VERSION 5.7 ;
  NOWIREEXTENSIONATPIN ON ;
  DIVIDERCHAR "/" ;
  BUSBITCHARS "[]" ;
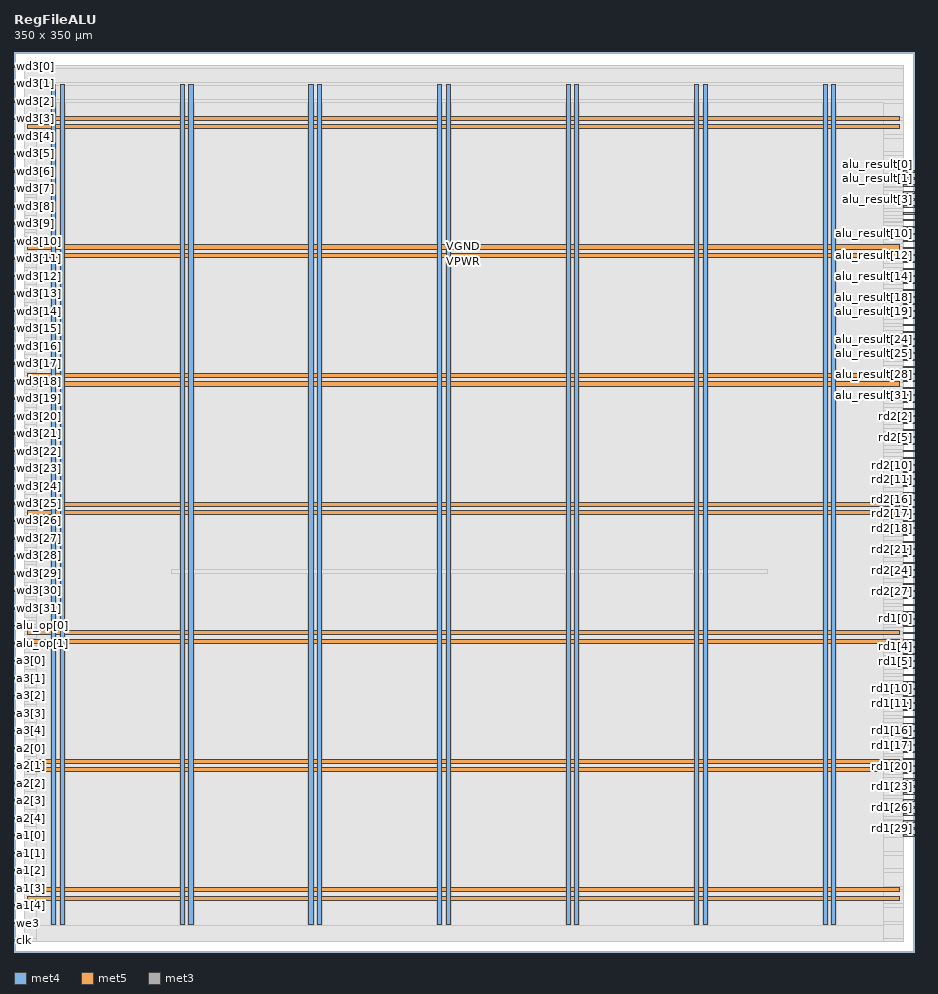
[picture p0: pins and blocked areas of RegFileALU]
MACRO RegFileALU
  CLASS BLOCK ;
  FOREIGN RegFileALU ;
  ORIGIN 0.000 0.000 ;
  SIZE 350.000 BY 350.000 ;
  PIN VGND
    DIRECTION INOUT ;
    USE GROUND ;
    PORT
      LAYER met4 ;
        RECT 18.020 10.640 19.620 337.520 ;
    END
    PORT
      LAYER met4 ;
        RECT 68.020 10.640 69.620 337.520 ;
    END
    PORT
      LAYER met4 ;
        RECT 118.020 10.640 119.620 337.520 ;
    END
    PORT
      LAYER met4 ;
        RECT 168.020 10.640 169.620 337.520 ;
    END
    PORT
      LAYER met4 ;
        RECT 218.020 10.640 219.620 337.520 ;
    END
    PORT
      LAYER met4 ;
        RECT 268.020 10.640 269.620 337.520 ;
    END
    PORT
      LAYER met4 ;
        RECT 318.020 10.640 319.620 337.520 ;
    END
    PORT
      LAYER met5 ;
        RECT 5.280 23.380 344.320 24.980 ;
    END
    PORT
      LAYER met5 ;
        RECT 5.280 73.380 344.320 74.980 ;
    END
    PORT
      LAYER met5 ;
        RECT 5.280 123.380 344.320 124.980 ;
    END
    PORT
      LAYER met5 ;
        RECT 5.280 173.380 344.320 174.980 ;
    END
    PORT
      LAYER met5 ;
        RECT 5.280 223.380 344.320 224.980 ;
    END
    PORT
      LAYER met5 ;
        RECT 5.280 273.380 344.320 274.980 ;
    END
    PORT
      LAYER met5 ;
        RECT 5.280 323.380 344.320 324.980 ;
    END
  END VGND
  PIN VPWR
    DIRECTION INOUT ;
    USE POWER ;
    PORT
      LAYER met4 ;
        RECT 14.720 10.640 16.320 337.520 ;
    END
    PORT
      LAYER met4 ;
        RECT 64.720 10.640 66.320 337.520 ;
    END
    PORT
      LAYER met4 ;
        RECT 114.720 10.640 116.320 337.520 ;
    END
    PORT
      LAYER met4 ;
        RECT 164.720 10.640 166.320 337.520 ;
    END
    PORT
      LAYER met4 ;
        RECT 214.720 10.640 216.320 337.520 ;
    END
    PORT
      LAYER met4 ;
        RECT 264.720 10.640 266.320 337.520 ;
    END
    PORT
      LAYER met4 ;
        RECT 314.720 10.640 316.320 337.520 ;
    END
    PORT
      LAYER met5 ;
        RECT 5.280 20.080 344.320 21.680 ;
    END
    PORT
      LAYER met5 ;
        RECT 5.280 70.080 344.320 71.680 ;
    END
    PORT
      LAYER met5 ;
        RECT 5.280 120.080 344.320 121.680 ;
    END
    PORT
      LAYER met5 ;
        RECT 5.280 170.080 344.320 171.680 ;
    END
    PORT
      LAYER met5 ;
        RECT 5.280 220.080 344.320 221.680 ;
    END
    PORT
      LAYER met5 ;
        RECT 5.280 270.080 344.320 271.680 ;
    END
    PORT
      LAYER met5 ;
        RECT 5.280 320.080 344.320 321.680 ;
    END
  END VPWR
  PIN a1[0]
    DIRECTION INPUT ;
    USE SIGNAL ;
    ANTENNAGATEAREA 0.196500 ;
    ANTENNADIFFAREA 0.434700 ;
    PORT
      LAYER met3 ;
        RECT 0.000 44.920 4.000 45.520 ;
    END
  END a1[0]
  PIN a1[1]
    DIRECTION INPUT ;
    USE SIGNAL ;
    ANTENNAGATEAREA 0.196500 ;
    ANTENNADIFFAREA 0.434700 ;
    PORT
      LAYER met3 ;
        RECT 0.000 38.120 4.000 38.720 ;
    END
  END a1[1]
  PIN a1[2]
    DIRECTION INPUT ;
    USE SIGNAL ;
    ANTENNAGATEAREA 0.126000 ;
    ANTENNADIFFAREA 0.434700 ;
    PORT
      LAYER met3 ;
        RECT 0.000 31.320 4.000 31.920 ;
    END
  END a1[2]
  PIN a1[3]
    DIRECTION INPUT ;
    USE SIGNAL ;
    ANTENNAGATEAREA 0.213000 ;
    ANTENNADIFFAREA 0.434700 ;
    PORT
      LAYER met3 ;
        RECT 0.000 24.520 4.000 25.120 ;
    END
  END a1[3]
  PIN a1[4]
    DIRECTION INPUT ;
    USE SIGNAL ;
    ANTENNAGATEAREA 0.213000 ;
    ANTENNADIFFAREA 0.434700 ;
    PORT
      LAYER met3 ;
        RECT 0.000 17.720 4.000 18.320 ;
    END
  END a1[4]
  PIN a2[0]
    DIRECTION INPUT ;
    USE SIGNAL ;
    ANTENNAGATEAREA 0.990000 ;
    ANTENNADIFFAREA 1.738800 ;
    PORT
      LAYER met3 ;
        RECT 0.000 78.920 4.000 79.520 ;
    END
  END a2[0]
  PIN a2[1]
    DIRECTION INPUT ;
    USE SIGNAL ;
    ANTENNAGATEAREA 0.852000 ;
    ANTENNADIFFAREA 1.738800 ;
    PORT
      LAYER met3 ;
        RECT 0.000 72.120 4.000 72.720 ;
    END
  END a2[1]
  PIN a2[2]
    DIRECTION INPUT ;
    USE SIGNAL ;
    ANTENNAGATEAREA 0.247500 ;
    ANTENNADIFFAREA 0.434700 ;
    PORT
      LAYER met3 ;
        RECT 0.000 65.320 4.000 65.920 ;
    END
  END a2[2]
  PIN a2[3]
    DIRECTION INPUT ;
    USE SIGNAL ;
    ANTENNAGATEAREA 0.213000 ;
    ANTENNADIFFAREA 0.434700 ;
    PORT
      LAYER met3 ;
        RECT 0.000 58.520 4.000 59.120 ;
    END
  END a2[3]
  PIN a2[4]
    DIRECTION INPUT ;
    USE SIGNAL ;
    ANTENNAGATEAREA 0.247500 ;
    ANTENNADIFFAREA 0.434700 ;
    PORT
      LAYER met3 ;
        RECT 0.000 51.720 4.000 52.320 ;
    END
  END a2[4]
  PIN a3[0]
    DIRECTION INPUT ;
    USE SIGNAL ;
    ANTENNAGATEAREA 0.213000 ;
    ANTENNADIFFAREA 0.434700 ;
    PORT
      LAYER met3 ;
        RECT 0.000 112.920 4.000 113.520 ;
    END
  END a3[0]
  PIN a3[1]
    DIRECTION INPUT ;
    USE SIGNAL ;
    ANTENNAGATEAREA 0.213000 ;
    ANTENNADIFFAREA 0.434700 ;
    PORT
      LAYER met3 ;
        RECT 0.000 106.120 4.000 106.720 ;
    END
  END a3[1]
  PIN a3[2]
    DIRECTION INPUT ;
    USE SIGNAL ;
    ANTENNAGATEAREA 0.213000 ;
    ANTENNADIFFAREA 0.434700 ;
    PORT
      LAYER met3 ;
        RECT 0.000 99.320 4.000 99.920 ;
    END
  END a3[2]
  PIN a3[3]
    DIRECTION INPUT ;
    USE SIGNAL ;
    ANTENNAGATEAREA 0.213000 ;
    ANTENNADIFFAREA 0.434700 ;
    PORT
      LAYER met3 ;
        RECT 0.000 92.520 4.000 93.120 ;
    END
  END a3[3]
  PIN a3[4]
    DIRECTION INPUT ;
    USE SIGNAL ;
    ANTENNAGATEAREA 0.213000 ;
    ANTENNADIFFAREA 0.434700 ;
    PORT
      LAYER met3 ;
        RECT 0.000 85.720 4.000 86.320 ;
    END
  END a3[4]
  PIN alu_op[0]
    DIRECTION INPUT ;
    USE SIGNAL ;
    ANTENNAGATEAREA 0.213000 ;
    ANTENNADIFFAREA 0.434700 ;
    PORT
      LAYER met3 ;
        RECT 0.000 126.520 4.000 127.120 ;
    END
  END alu_op[0]
  PIN alu_op[1]
    DIRECTION INPUT ;
    USE SIGNAL ;
    ANTENNAGATEAREA 0.247500 ;
    ANTENNADIFFAREA 0.434700 ;
    PORT
      LAYER met3 ;
        RECT 0.000 119.720 4.000 120.320 ;
    END
  END alu_op[1]
  PIN alu_result[0]
    DIRECTION OUTPUT ;
    USE SIGNAL ;
    ANTENNADIFFAREA 0.340600 ;
    PORT
      LAYER met3 ;
        RECT 346.000 303.320 350.000 303.920 ;
    END
  END alu_result[0]
  PIN alu_result[10]
    DIRECTION OUTPUT ;
    USE SIGNAL ;
    ANTENNADIFFAREA 0.340600 ;
    PORT
      LAYER met3 ;
        RECT 346.000 276.120 350.000 276.720 ;
    END
  END alu_result[10]
  PIN alu_result[11]
    DIRECTION OUTPUT ;
    USE SIGNAL ;
    ANTENNADIFFAREA 0.340600 ;
    PORT
      LAYER met3 ;
        RECT 346.000 273.400 350.000 274.000 ;
    END
  END alu_result[11]
  PIN alu_result[12]
    DIRECTION OUTPUT ;
    USE SIGNAL ;
    ANTENNADIFFAREA 0.340600 ;
    PORT
      LAYER met3 ;
        RECT 346.000 270.680 350.000 271.280 ;
    END
  END alu_result[12]
  PIN alu_result[13]
    DIRECTION OUTPUT ;
    USE SIGNAL ;
    ANTENNADIFFAREA 0.340600 ;
    PORT
      LAYER met3 ;
        RECT 346.000 267.960 350.000 268.560 ;
    END
  END alu_result[13]
  PIN alu_result[14]
    DIRECTION OUTPUT ;
    USE SIGNAL ;
    ANTENNADIFFAREA 0.340600 ;
    PORT
      LAYER met3 ;
        RECT 346.000 265.240 350.000 265.840 ;
    END
  END alu_result[14]
  PIN alu_result[15]
    DIRECTION OUTPUT ;
    USE SIGNAL ;
    ANTENNADIFFAREA 0.340600 ;
    PORT
      LAYER met3 ;
        RECT 346.000 262.520 350.000 263.120 ;
    END
  END alu_result[15]
  PIN alu_result[16]
    DIRECTION OUTPUT ;
    USE SIGNAL ;
    ANTENNADIFFAREA 0.340600 ;
    PORT
      LAYER met3 ;
        RECT 346.000 259.800 350.000 260.400 ;
    END
  END alu_result[16]
  PIN alu_result[17]
    DIRECTION OUTPUT ;
    USE SIGNAL ;
    ANTENNADIFFAREA 0.340600 ;
    PORT
      LAYER met3 ;
        RECT 346.000 257.080 350.000 257.680 ;
    END
  END alu_result[17]
  PIN alu_result[18]
    DIRECTION OUTPUT ;
    USE SIGNAL ;
    ANTENNADIFFAREA 0.340600 ;
    PORT
      LAYER met3 ;
        RECT 346.000 254.360 350.000 254.960 ;
    END
  END alu_result[18]
  PIN alu_result[19]
    DIRECTION OUTPUT ;
    USE SIGNAL ;
    ANTENNADIFFAREA 0.340600 ;
    PORT
      LAYER met3 ;
        RECT 346.000 251.640 350.000 252.240 ;
    END
  END alu_result[19]
  PIN alu_result[1]
    DIRECTION OUTPUT ;
    USE SIGNAL ;
    ANTENNADIFFAREA 0.340600 ;
    PORT
      LAYER met3 ;
        RECT 346.000 300.600 350.000 301.200 ;
    END
  END alu_result[1]
  PIN alu_result[20]
    DIRECTION OUTPUT ;
    USE SIGNAL ;
    ANTENNADIFFAREA 0.340600 ;
    PORT
      LAYER met3 ;
        RECT 346.000 248.920 350.000 249.520 ;
    END
  END alu_result[20]
  PIN alu_result[21]
    DIRECTION OUTPUT ;
    USE SIGNAL ;
    ANTENNADIFFAREA 0.340600 ;
    PORT
      LAYER met3 ;
        RECT 346.000 246.200 350.000 246.800 ;
    END
  END alu_result[21]
  PIN alu_result[22]
    DIRECTION OUTPUT ;
    USE SIGNAL ;
    ANTENNADIFFAREA 0.340600 ;
    PORT
      LAYER met3 ;
        RECT 346.000 243.480 350.000 244.080 ;
    END
  END alu_result[22]
  PIN alu_result[23]
    DIRECTION OUTPUT ;
    USE SIGNAL ;
    ANTENNADIFFAREA 0.340600 ;
    PORT
      LAYER met3 ;
        RECT 346.000 240.760 350.000 241.360 ;
    END
  END alu_result[23]
  PIN alu_result[24]
    DIRECTION OUTPUT ;
    USE SIGNAL ;
    ANTENNADIFFAREA 0.340600 ;
    PORT
      LAYER met3 ;
        RECT 346.000 238.040 350.000 238.640 ;
    END
  END alu_result[24]
  PIN alu_result[25]
    DIRECTION OUTPUT ;
    USE SIGNAL ;
    ANTENNADIFFAREA 0.340600 ;
    PORT
      LAYER met3 ;
        RECT 346.000 235.320 350.000 235.920 ;
    END
  END alu_result[25]
  PIN alu_result[26]
    DIRECTION OUTPUT ;
    USE SIGNAL ;
    ANTENNADIFFAREA 0.340600 ;
    PORT
      LAYER met3 ;
        RECT 346.000 232.600 350.000 233.200 ;
    END
  END alu_result[26]
  PIN alu_result[27]
    DIRECTION OUTPUT ;
    USE SIGNAL ;
    ANTENNADIFFAREA 0.340600 ;
    PORT
      LAYER met3 ;
        RECT 346.000 229.880 350.000 230.480 ;
    END
  END alu_result[27]
  PIN alu_result[28]
    DIRECTION OUTPUT ;
    USE SIGNAL ;
    ANTENNADIFFAREA 0.340600 ;
    PORT
      LAYER met3 ;
        RECT 346.000 227.160 350.000 227.760 ;
    END
  END alu_result[28]
  PIN alu_result[29]
    DIRECTION OUTPUT ;
    USE SIGNAL ;
    ANTENNADIFFAREA 0.340600 ;
    PORT
      LAYER met3 ;
        RECT 346.000 224.440 350.000 225.040 ;
    END
  END alu_result[29]
  PIN alu_result[2]
    DIRECTION OUTPUT ;
    USE SIGNAL ;
    ANTENNADIFFAREA 0.340600 ;
    PORT
      LAYER met3 ;
        RECT 346.000 297.880 350.000 298.480 ;
    END
  END alu_result[2]
  PIN alu_result[30]
    DIRECTION OUTPUT ;
    USE SIGNAL ;
    ANTENNADIFFAREA 0.340600 ;
    PORT
      LAYER met3 ;
        RECT 346.000 221.720 350.000 222.320 ;
    END
  END alu_result[30]
  PIN alu_result[31]
    DIRECTION OUTPUT ;
    USE SIGNAL ;
    ANTENNADIFFAREA 0.340600 ;
    PORT
      LAYER met3 ;
        RECT 346.000 219.000 350.000 219.600 ;
    END
  END alu_result[31]
  PIN alu_result[3]
    DIRECTION OUTPUT ;
    USE SIGNAL ;
    ANTENNADIFFAREA 0.340600 ;
    PORT
      LAYER met3 ;
        RECT 346.000 295.160 350.000 295.760 ;
    END
  END alu_result[3]
  PIN alu_result[4]
    DIRECTION OUTPUT ;
    USE SIGNAL ;
    ANTENNADIFFAREA 0.340600 ;
    PORT
      LAYER met3 ;
        RECT 346.000 292.440 350.000 293.040 ;
    END
  END alu_result[4]
  PIN alu_result[5]
    DIRECTION OUTPUT ;
    USE SIGNAL ;
    ANTENNADIFFAREA 0.340600 ;
    PORT
      LAYER met3 ;
        RECT 346.000 289.720 350.000 290.320 ;
    END
  END alu_result[5]
  PIN alu_result[6]
    DIRECTION OUTPUT ;
    USE SIGNAL ;
    ANTENNADIFFAREA 0.340600 ;
    PORT
      LAYER met3 ;
        RECT 346.000 287.000 350.000 287.600 ;
    END
  END alu_result[6]
  PIN alu_result[7]
    DIRECTION OUTPUT ;
    USE SIGNAL ;
    ANTENNADIFFAREA 0.340600 ;
    PORT
      LAYER met3 ;
        RECT 346.000 284.280 350.000 284.880 ;
    END
  END alu_result[7]
  PIN alu_result[8]
    DIRECTION OUTPUT ;
    USE SIGNAL ;
    ANTENNADIFFAREA 0.340600 ;
    PORT
      LAYER met3 ;
        RECT 346.000 281.560 350.000 282.160 ;
    END
  END alu_result[8]
  PIN alu_result[9]
    DIRECTION OUTPUT ;
    USE SIGNAL ;
    ANTENNADIFFAREA 0.340600 ;
    PORT
      LAYER met3 ;
        RECT 346.000 278.840 350.000 279.440 ;
    END
  END alu_result[9]
  PIN clk
    DIRECTION INPUT ;
    USE SIGNAL ;
    ANTENNAGATEAREA 0.852000 ;
    ANTENNADIFFAREA 0.434700 ;
    PORT
      LAYER met3 ;
        RECT 0.000 4.120 4.000 4.720 ;
    END
  END clk
  PIN rd1[0]
    DIRECTION OUTPUT ;
    USE SIGNAL ;
    ANTENNADIFFAREA 0.340600 ;
    PORT
      LAYER met3 ;
        RECT 346.000 129.240 350.000 129.840 ;
    END
  END rd1[0]
  PIN rd1[10]
    DIRECTION OUTPUT ;
    USE SIGNAL ;
    ANTENNADIFFAREA 0.340600 ;
    PORT
      LAYER met3 ;
        RECT 346.000 102.040 350.000 102.640 ;
    END
  END rd1[10]
  PIN rd1[11]
    DIRECTION OUTPUT ;
    USE SIGNAL ;
    ANTENNADIFFAREA 0.340600 ;
    PORT
      LAYER met3 ;
        RECT 346.000 99.320 350.000 99.920 ;
    END
  END rd1[11]
  PIN rd1[12]
    DIRECTION OUTPUT ;
    USE SIGNAL ;
    ANTENNADIFFAREA 0.340600 ;
    PORT
      LAYER met3 ;
        RECT 346.000 96.600 350.000 97.200 ;
    END
  END rd1[12]
  PIN rd1[13]
    DIRECTION OUTPUT ;
    USE SIGNAL ;
    ANTENNADIFFAREA 0.340600 ;
    PORT
      LAYER met3 ;
        RECT 346.000 93.880 350.000 94.480 ;
    END
  END rd1[13]
  PIN rd1[14]
    DIRECTION OUTPUT ;
    USE SIGNAL ;
    ANTENNADIFFAREA 0.340600 ;
    PORT
      LAYER met3 ;
        RECT 346.000 91.160 350.000 91.760 ;
    END
  END rd1[14]
  PIN rd1[15]
    DIRECTION OUTPUT ;
    USE SIGNAL ;
    ANTENNADIFFAREA 0.340600 ;
    PORT
      LAYER met3 ;
        RECT 346.000 88.440 350.000 89.040 ;
    END
  END rd1[15]
  PIN rd1[16]
    DIRECTION OUTPUT ;
    USE SIGNAL ;
    ANTENNADIFFAREA 0.340600 ;
    PORT
      LAYER met3 ;
        RECT 346.000 85.720 350.000 86.320 ;
    END
  END rd1[16]
  PIN rd1[17]
    DIRECTION OUTPUT ;
    USE SIGNAL ;
    ANTENNADIFFAREA 0.340600 ;
    PORT
      LAYER met3 ;
        RECT 346.000 83.000 350.000 83.600 ;
    END
  END rd1[17]
  PIN rd1[18]
    DIRECTION OUTPUT ;
    USE SIGNAL ;
    ANTENNADIFFAREA 0.340600 ;
    PORT
      LAYER met3 ;
        RECT 346.000 80.280 350.000 80.880 ;
    END
  END rd1[18]
  PIN rd1[19]
    DIRECTION OUTPUT ;
    USE SIGNAL ;
    ANTENNADIFFAREA 0.340600 ;
    PORT
      LAYER met3 ;
        RECT 346.000 77.560 350.000 78.160 ;
    END
  END rd1[19]
  PIN rd1[1]
    DIRECTION OUTPUT ;
    USE SIGNAL ;
    ANTENNADIFFAREA 0.340600 ;
    PORT
      LAYER met3 ;
        RECT 346.000 126.520 350.000 127.120 ;
    END
  END rd1[1]
  PIN rd1[20]
    DIRECTION OUTPUT ;
    USE SIGNAL ;
    ANTENNADIFFAREA 0.340600 ;
    PORT
      LAYER met3 ;
        RECT 346.000 74.840 350.000 75.440 ;
    END
  END rd1[20]
  PIN rd1[21]
    DIRECTION OUTPUT ;
    USE SIGNAL ;
    ANTENNADIFFAREA 0.340600 ;
    PORT
      LAYER met3 ;
        RECT 346.000 72.120 350.000 72.720 ;
    END
  END rd1[21]
  PIN rd1[22]
    DIRECTION OUTPUT ;
    USE SIGNAL ;
    ANTENNADIFFAREA 0.340600 ;
    PORT
      LAYER met3 ;
        RECT 346.000 69.400 350.000 70.000 ;
    END
  END rd1[22]
  PIN rd1[23]
    DIRECTION OUTPUT ;
    USE SIGNAL ;
    ANTENNADIFFAREA 0.340600 ;
    PORT
      LAYER met3 ;
        RECT 346.000 66.680 350.000 67.280 ;
    END
  END rd1[23]
  PIN rd1[24]
    DIRECTION OUTPUT ;
    USE SIGNAL ;
    ANTENNADIFFAREA 0.340600 ;
    PORT
      LAYER met3 ;
        RECT 346.000 63.960 350.000 64.560 ;
    END
  END rd1[24]
  PIN rd1[25]
    DIRECTION OUTPUT ;
    USE SIGNAL ;
    ANTENNADIFFAREA 0.340600 ;
    PORT
      LAYER met3 ;
        RECT 346.000 61.240 350.000 61.840 ;
    END
  END rd1[25]
  PIN rd1[26]
    DIRECTION OUTPUT ;
    USE SIGNAL ;
    ANTENNADIFFAREA 0.340600 ;
    PORT
      LAYER met3 ;
        RECT 346.000 58.520 350.000 59.120 ;
    END
  END rd1[26]
  PIN rd1[27]
    DIRECTION OUTPUT ;
    USE SIGNAL ;
    ANTENNADIFFAREA 0.340600 ;
    PORT
      LAYER met3 ;
        RECT 346.000 55.800 350.000 56.400 ;
    END
  END rd1[27]
  PIN rd1[28]
    DIRECTION OUTPUT ;
    USE SIGNAL ;
    ANTENNADIFFAREA 0.340600 ;
    PORT
      LAYER met3 ;
        RECT 346.000 53.080 350.000 53.680 ;
    END
  END rd1[28]
  PIN rd1[29]
    DIRECTION OUTPUT ;
    USE SIGNAL ;
    ANTENNADIFFAREA 0.340600 ;
    PORT
      LAYER met3 ;
        RECT 346.000 50.360 350.000 50.960 ;
    END
  END rd1[29]
  PIN rd1[2]
    DIRECTION OUTPUT ;
    USE SIGNAL ;
    ANTENNADIFFAREA 0.340600 ;
    PORT
      LAYER met3 ;
        RECT 346.000 123.800 350.000 124.400 ;
    END
  END rd1[2]
  PIN rd1[30]
    DIRECTION OUTPUT ;
    USE SIGNAL ;
    ANTENNADIFFAREA 0.340600 ;
    PORT
      LAYER met3 ;
        RECT 346.000 47.640 350.000 48.240 ;
    END
  END rd1[30]
  PIN rd1[31]
    DIRECTION OUTPUT ;
    USE SIGNAL ;
    ANTENNADIFFAREA 0.340600 ;
    PORT
      LAYER met3 ;
        RECT 346.000 44.920 350.000 45.520 ;
    END
  END rd1[31]
  PIN rd1[3]
    DIRECTION OUTPUT ;
    USE SIGNAL ;
    ANTENNADIFFAREA 0.340600 ;
    PORT
      LAYER met3 ;
        RECT 346.000 121.080 350.000 121.680 ;
    END
  END rd1[3]
  PIN rd1[4]
    DIRECTION OUTPUT ;
    USE SIGNAL ;
    ANTENNADIFFAREA 0.340600 ;
    PORT
      LAYER met3 ;
        RECT 346.000 118.360 350.000 118.960 ;
    END
  END rd1[4]
  PIN rd1[5]
    DIRECTION OUTPUT ;
    USE SIGNAL ;
    ANTENNADIFFAREA 0.340600 ;
    PORT
      LAYER met3 ;
        RECT 346.000 115.640 350.000 116.240 ;
    END
  END rd1[5]
  PIN rd1[6]
    DIRECTION OUTPUT ;
    USE SIGNAL ;
    ANTENNADIFFAREA 0.340600 ;
    PORT
      LAYER met3 ;
        RECT 346.000 112.920 350.000 113.520 ;
    END
  END rd1[6]
  PIN rd1[7]
    DIRECTION OUTPUT ;
    USE SIGNAL ;
    ANTENNADIFFAREA 0.340600 ;
    PORT
      LAYER met3 ;
        RECT 346.000 110.200 350.000 110.800 ;
    END
  END rd1[7]
  PIN rd1[8]
    DIRECTION OUTPUT ;
    USE SIGNAL ;
    ANTENNADIFFAREA 0.340600 ;
    PORT
      LAYER met3 ;
        RECT 346.000 107.480 350.000 108.080 ;
    END
  END rd1[8]
  PIN rd1[9]
    DIRECTION OUTPUT ;
    USE SIGNAL ;
    ANTENNADIFFAREA 0.340600 ;
    PORT
      LAYER met3 ;
        RECT 346.000 104.760 350.000 105.360 ;
    END
  END rd1[9]
  PIN rd2[0]
    DIRECTION OUTPUT ;
    USE SIGNAL ;
    ANTENNADIFFAREA 0.340600 ;
    PORT
      LAYER met3 ;
        RECT 346.000 216.280 350.000 216.880 ;
    END
  END rd2[0]
  PIN rd2[10]
    DIRECTION OUTPUT ;
    USE SIGNAL ;
    ANTENNADIFFAREA 0.340600 ;
    PORT
      LAYER met3 ;
        RECT 346.000 189.080 350.000 189.680 ;
    END
  END rd2[10]
  PIN rd2[11]
    DIRECTION OUTPUT ;
    USE SIGNAL ;
    ANTENNADIFFAREA 0.340600 ;
    PORT
      LAYER met3 ;
        RECT 346.000 186.360 350.000 186.960 ;
    END
  END rd2[11]
  PIN rd2[12]
    DIRECTION OUTPUT ;
    USE SIGNAL ;
    ANTENNADIFFAREA 0.340600 ;
    PORT
      LAYER met3 ;
        RECT 346.000 183.640 350.000 184.240 ;
    END
  END rd2[12]
  PIN rd2[13]
    DIRECTION OUTPUT ;
    USE SIGNAL ;
    ANTENNADIFFAREA 0.340600 ;
    PORT
      LAYER met3 ;
        RECT 346.000 180.920 350.000 181.520 ;
    END
  END rd2[13]
  PIN rd2[14]
    DIRECTION OUTPUT ;
    USE SIGNAL ;
    ANTENNADIFFAREA 0.340600 ;
    PORT
      LAYER met3 ;
        RECT 346.000 178.200 350.000 178.800 ;
    END
  END rd2[14]
  PIN rd2[15]
    DIRECTION OUTPUT ;
    USE SIGNAL ;
    ANTENNADIFFAREA 0.340600 ;
    PORT
      LAYER met3 ;
        RECT 346.000 175.480 350.000 176.080 ;
    END
  END rd2[15]
  PIN rd2[16]
    DIRECTION OUTPUT ;
    USE SIGNAL ;
    ANTENNADIFFAREA 0.340600 ;
    PORT
      LAYER met3 ;
        RECT 346.000 172.760 350.000 173.360 ;
    END
  END rd2[16]
  PIN rd2[17]
    DIRECTION OUTPUT ;
    USE SIGNAL ;
    ANTENNADIFFAREA 0.340600 ;
    PORT
      LAYER met3 ;
        RECT 346.000 170.040 350.000 170.640 ;
    END
  END rd2[17]
  PIN rd2[18]
    DIRECTION OUTPUT ;
    USE SIGNAL ;
    ANTENNADIFFAREA 0.340600 ;
    PORT
      LAYER met3 ;
        RECT 346.000 167.320 350.000 167.920 ;
    END
  END rd2[18]
  PIN rd2[19]
    DIRECTION OUTPUT ;
    USE SIGNAL ;
    ANTENNADIFFAREA 0.340600 ;
    PORT
      LAYER met3 ;
        RECT 346.000 164.600 350.000 165.200 ;
    END
  END rd2[19]
  PIN rd2[1]
    DIRECTION OUTPUT ;
    USE SIGNAL ;
    ANTENNADIFFAREA 0.340600 ;
    PORT
      LAYER met3 ;
        RECT 346.000 213.560 350.000 214.160 ;
    END
  END rd2[1]
  PIN rd2[20]
    DIRECTION OUTPUT ;
    USE SIGNAL ;
    ANTENNADIFFAREA 0.340600 ;
    PORT
      LAYER met3 ;
        RECT 346.000 161.880 350.000 162.480 ;
    END
  END rd2[20]
  PIN rd2[21]
    DIRECTION OUTPUT ;
    USE SIGNAL ;
    ANTENNADIFFAREA 0.340600 ;
    PORT
      LAYER met3 ;
        RECT 346.000 159.160 350.000 159.760 ;
    END
  END rd2[21]
  PIN rd2[22]
    DIRECTION OUTPUT ;
    USE SIGNAL ;
    ANTENNADIFFAREA 0.340600 ;
    PORT
      LAYER met3 ;
        RECT 346.000 156.440 350.000 157.040 ;
    END
  END rd2[22]
  PIN rd2[23]
    DIRECTION OUTPUT ;
    USE SIGNAL ;
    ANTENNADIFFAREA 0.340600 ;
    PORT
      LAYER met3 ;
        RECT 346.000 153.720 350.000 154.320 ;
    END
  END rd2[23]
  PIN rd2[24]
    DIRECTION OUTPUT ;
    USE SIGNAL ;
    ANTENNADIFFAREA 0.340600 ;
    PORT
      LAYER met3 ;
        RECT 346.000 151.000 350.000 151.600 ;
    END
  END rd2[24]
  PIN rd2[25]
    DIRECTION OUTPUT ;
    USE SIGNAL ;
    ANTENNADIFFAREA 0.340600 ;
    PORT
      LAYER met3 ;
        RECT 346.000 148.280 350.000 148.880 ;
    END
  END rd2[25]
  PIN rd2[26]
    DIRECTION OUTPUT ;
    USE SIGNAL ;
    ANTENNADIFFAREA 0.340600 ;
    PORT
      LAYER met3 ;
        RECT 346.000 145.560 350.000 146.160 ;
    END
  END rd2[26]
  PIN rd2[27]
    DIRECTION OUTPUT ;
    USE SIGNAL ;
    ANTENNADIFFAREA 0.340600 ;
    PORT
      LAYER met3 ;
        RECT 346.000 142.840 350.000 143.440 ;
    END
  END rd2[27]
  PIN rd2[28]
    DIRECTION OUTPUT ;
    USE SIGNAL ;
    ANTENNADIFFAREA 0.340600 ;
    PORT
      LAYER met3 ;
        RECT 346.000 140.120 350.000 140.720 ;
    END
  END rd2[28]
  PIN rd2[29]
    DIRECTION OUTPUT ;
    USE SIGNAL ;
    ANTENNADIFFAREA 0.340600 ;
    PORT
      LAYER met3 ;
        RECT 346.000 137.400 350.000 138.000 ;
    END
  END rd2[29]
  PIN rd2[2]
    DIRECTION OUTPUT ;
    USE SIGNAL ;
    ANTENNADIFFAREA 0.340600 ;
    PORT
      LAYER met3 ;
        RECT 346.000 210.840 350.000 211.440 ;
    END
  END rd2[2]
  PIN rd2[30]
    DIRECTION OUTPUT ;
    USE SIGNAL ;
    ANTENNADIFFAREA 0.340600 ;
    PORT
      LAYER met3 ;
        RECT 346.000 134.680 350.000 135.280 ;
    END
  END rd2[30]
  PIN rd2[31]
    DIRECTION OUTPUT ;
    USE SIGNAL ;
    ANTENNADIFFAREA 0.340600 ;
    PORT
      LAYER met3 ;
        RECT 346.000 131.960 350.000 132.560 ;
    END
  END rd2[31]
  PIN rd2[3]
    DIRECTION OUTPUT ;
    USE SIGNAL ;
    ANTENNADIFFAREA 0.340600 ;
    PORT
      LAYER met3 ;
        RECT 346.000 208.120 350.000 208.720 ;
    END
  END rd2[3]
  PIN rd2[4]
    DIRECTION OUTPUT ;
    USE SIGNAL ;
    ANTENNADIFFAREA 0.340600 ;
    PORT
      LAYER met3 ;
        RECT 346.000 205.400 350.000 206.000 ;
    END
  END rd2[4]
  PIN rd2[5]
    DIRECTION OUTPUT ;
    USE SIGNAL ;
    ANTENNADIFFAREA 0.340600 ;
    PORT
      LAYER met3 ;
        RECT 346.000 202.680 350.000 203.280 ;
    END
  END rd2[5]
  PIN rd2[6]
    DIRECTION OUTPUT ;
    USE SIGNAL ;
    ANTENNADIFFAREA 0.340600 ;
    PORT
      LAYER met3 ;
        RECT 346.000 199.960 350.000 200.560 ;
    END
  END rd2[6]
  PIN rd2[7]
    DIRECTION OUTPUT ;
    USE SIGNAL ;
    ANTENNADIFFAREA 0.340600 ;
    PORT
      LAYER met3 ;
        RECT 346.000 197.240 350.000 197.840 ;
    END
  END rd2[7]
  PIN rd2[8]
    DIRECTION OUTPUT ;
    USE SIGNAL ;
    ANTENNADIFFAREA 0.340600 ;
    PORT
      LAYER met3 ;
        RECT 346.000 194.520 350.000 195.120 ;
    END
  END rd2[8]
  PIN rd2[9]
    DIRECTION OUTPUT ;
    USE SIGNAL ;
    ANTENNADIFFAREA 0.340600 ;
    PORT
      LAYER met3 ;
        RECT 346.000 191.800 350.000 192.400 ;
    END
  END rd2[9]
  PIN wd3[0]
    DIRECTION INPUT ;
    USE SIGNAL ;
    ANTENNAGATEAREA 0.159000 ;
    ANTENNADIFFAREA 0.434700 ;
    PORT
      LAYER met3 ;
        RECT 0.000 344.120 4.000 344.720 ;
    END
  END wd3[0]
  PIN wd3[10]
    DIRECTION INPUT ;
    USE SIGNAL ;
    ANTENNAGATEAREA 0.213000 ;
    ANTENNADIFFAREA 0.434700 ;
    PORT
      LAYER met3 ;
        RECT 0.000 276.120 4.000 276.720 ;
    END
  END wd3[10]
  PIN wd3[11]
    DIRECTION INPUT ;
    USE SIGNAL ;
    ANTENNAGATEAREA 0.159000 ;
    ANTENNADIFFAREA 0.434700 ;
    PORT
      LAYER met3 ;
        RECT 0.000 269.320 4.000 269.920 ;
    END
  END wd3[11]
  PIN wd3[12]
    DIRECTION INPUT ;
    USE SIGNAL ;
    ANTENNAGATEAREA 0.213000 ;
    ANTENNADIFFAREA 0.434700 ;
    PORT
      LAYER met3 ;
        RECT 0.000 262.520 4.000 263.120 ;
    END
  END wd3[12]
  PIN wd3[13]
    DIRECTION INPUT ;
    USE SIGNAL ;
    ANTENNAGATEAREA 0.159000 ;
    ANTENNADIFFAREA 0.434700 ;
    PORT
      LAYER met3 ;
        RECT 0.000 255.720 4.000 256.320 ;
    END
  END wd3[13]
  PIN wd3[14]
    DIRECTION INPUT ;
    USE SIGNAL ;
    ANTENNAGATEAREA 0.213000 ;
    ANTENNADIFFAREA 0.434700 ;
    PORT
      LAYER met3 ;
        RECT 0.000 248.920 4.000 249.520 ;
    END
  END wd3[14]
  PIN wd3[15]
    DIRECTION INPUT ;
    USE SIGNAL ;
    ANTENNAGATEAREA 0.159000 ;
    ANTENNADIFFAREA 0.434700 ;
    PORT
      LAYER met3 ;
        RECT 0.000 242.120 4.000 242.720 ;
    END
  END wd3[15]
  PIN wd3[16]
    DIRECTION INPUT ;
    USE SIGNAL ;
    ANTENNAGATEAREA 0.159000 ;
    ANTENNADIFFAREA 0.434700 ;
    PORT
      LAYER met3 ;
        RECT 0.000 235.320 4.000 235.920 ;
    END
  END wd3[16]
  PIN wd3[17]
    DIRECTION INPUT ;
    USE SIGNAL ;
    ANTENNAGATEAREA 0.159000 ;
    ANTENNADIFFAREA 0.434700 ;
    PORT
      LAYER met3 ;
        RECT 0.000 228.520 4.000 229.120 ;
    END
  END wd3[17]
  PIN wd3[18]
    DIRECTION INPUT ;
    USE SIGNAL ;
    ANTENNAGATEAREA 0.159000 ;
    ANTENNADIFFAREA 0.434700 ;
    PORT
      LAYER met3 ;
        RECT 0.000 221.720 4.000 222.320 ;
    END
  END wd3[18]
  PIN wd3[19]
    DIRECTION INPUT ;
    USE SIGNAL ;
    ANTENNAGATEAREA 0.213000 ;
    ANTENNADIFFAREA 0.434700 ;
    PORT
      LAYER met3 ;
        RECT 0.000 214.920 4.000 215.520 ;
    END
  END wd3[19]
  PIN wd3[1]
    DIRECTION INPUT ;
    USE SIGNAL ;
    ANTENNAGATEAREA 0.159000 ;
    ANTENNADIFFAREA 0.434700 ;
    PORT
      LAYER met3 ;
        RECT 0.000 337.320 4.000 337.920 ;
    END
  END wd3[1]
  PIN wd3[20]
    DIRECTION INPUT ;
    USE SIGNAL ;
    ANTENNAGATEAREA 0.213000 ;
    ANTENNADIFFAREA 0.434700 ;
    PORT
      LAYER met3 ;
        RECT 0.000 208.120 4.000 208.720 ;
    END
  END wd3[20]
  PIN wd3[21]
    DIRECTION INPUT ;
    USE SIGNAL ;
    ANTENNAGATEAREA 0.213000 ;
    ANTENNADIFFAREA 0.434700 ;
    PORT
      LAYER met3 ;
        RECT 0.000 201.320 4.000 201.920 ;
    END
  END wd3[21]
  PIN wd3[22]
    DIRECTION INPUT ;
    USE SIGNAL ;
    ANTENNAGATEAREA 0.159000 ;
    ANTENNADIFFAREA 0.434700 ;
    PORT
      LAYER met3 ;
        RECT 0.000 194.520 4.000 195.120 ;
    END
  END wd3[22]
  PIN wd3[23]
    DIRECTION INPUT ;
    USE SIGNAL ;
    ANTENNAGATEAREA 0.213000 ;
    ANTENNADIFFAREA 0.434700 ;
    PORT
      LAYER met3 ;
        RECT 0.000 187.720 4.000 188.320 ;
    END
  END wd3[23]
  PIN wd3[24]
    DIRECTION INPUT ;
    USE SIGNAL ;
    ANTENNAGATEAREA 0.213000 ;
    ANTENNADIFFAREA 0.434700 ;
    PORT
      LAYER met3 ;
        RECT 0.000 180.920 4.000 181.520 ;
    END
  END wd3[24]
  PIN wd3[25]
    DIRECTION INPUT ;
    USE SIGNAL ;
    ANTENNAGATEAREA 0.213000 ;
    ANTENNADIFFAREA 0.434700 ;
    PORT
      LAYER met3 ;
        RECT 0.000 174.120 4.000 174.720 ;
    END
  END wd3[25]
  PIN wd3[26]
    DIRECTION INPUT ;
    USE SIGNAL ;
    ANTENNAGATEAREA 0.213000 ;
    ANTENNADIFFAREA 0.434700 ;
    PORT
      LAYER met3 ;
        RECT 0.000 167.320 4.000 167.920 ;
    END
  END wd3[26]
  PIN wd3[27]
    DIRECTION INPUT ;
    USE SIGNAL ;
    ANTENNAGATEAREA 0.159000 ;
    ANTENNADIFFAREA 0.434700 ;
    PORT
      LAYER met3 ;
        RECT 0.000 160.520 4.000 161.120 ;
    END
  END wd3[27]
  PIN wd3[28]
    DIRECTION INPUT ;
    USE SIGNAL ;
    ANTENNAGATEAREA 0.159000 ;
    ANTENNADIFFAREA 0.434700 ;
    PORT
      LAYER met3 ;
        RECT 0.000 153.720 4.000 154.320 ;
    END
  END wd3[28]
  PIN wd3[29]
    DIRECTION INPUT ;
    USE SIGNAL ;
    ANTENNAGATEAREA 0.159000 ;
    ANTENNADIFFAREA 0.434700 ;
    PORT
      LAYER met3 ;
        RECT 0.000 146.920 4.000 147.520 ;
    END
  END wd3[29]
  PIN wd3[2]
    DIRECTION INPUT ;
    USE SIGNAL ;
    ANTENNAGATEAREA 0.159000 ;
    ANTENNADIFFAREA 0.434700 ;
    PORT
      LAYER met3 ;
        RECT 0.000 330.520 4.000 331.120 ;
    END
  END wd3[2]
  PIN wd3[30]
    DIRECTION INPUT ;
    USE SIGNAL ;
    ANTENNAGATEAREA 0.213000 ;
    ANTENNADIFFAREA 0.434700 ;
    PORT
      LAYER met3 ;
        RECT 0.000 140.120 4.000 140.720 ;
    END
  END wd3[30]
  PIN wd3[31]
    DIRECTION INPUT ;
    USE SIGNAL ;
    ANTENNAGATEAREA 0.213000 ;
    ANTENNADIFFAREA 0.434700 ;
    PORT
      LAYER met3 ;
        RECT 0.000 133.320 4.000 133.920 ;
    END
  END wd3[31]
  PIN wd3[3]
    DIRECTION INPUT ;
    USE SIGNAL ;
    ANTENNAGATEAREA 0.213000 ;
    ANTENNADIFFAREA 0.434700 ;
    PORT
      LAYER met3 ;
        RECT 0.000 323.720 4.000 324.320 ;
    END
  END wd3[3]
  PIN wd3[4]
    DIRECTION INPUT ;
    USE SIGNAL ;
    ANTENNAGATEAREA 0.196500 ;
    ANTENNADIFFAREA 0.434700 ;
    PORT
      LAYER met3 ;
        RECT 0.000 316.920 4.000 317.520 ;
    END
  END wd3[4]
  PIN wd3[5]
    DIRECTION INPUT ;
    USE SIGNAL ;
    ANTENNAGATEAREA 0.126000 ;
    ANTENNADIFFAREA 0.434700 ;
    PORT
      LAYER met3 ;
        RECT 0.000 310.120 4.000 310.720 ;
    END
  END wd3[5]
  PIN wd3[6]
    DIRECTION INPUT ;
    USE SIGNAL ;
    ANTENNAGATEAREA 0.213000 ;
    ANTENNADIFFAREA 0.434700 ;
    PORT
      LAYER met3 ;
        RECT 0.000 303.320 4.000 303.920 ;
    END
  END wd3[6]
  PIN wd3[7]
    DIRECTION INPUT ;
    USE SIGNAL ;
    ANTENNAGATEAREA 0.126000 ;
    ANTENNADIFFAREA 0.434700 ;
    PORT
      LAYER met3 ;
        RECT 0.000 296.520 4.000 297.120 ;
    END
  END wd3[7]
  PIN wd3[8]
    DIRECTION INPUT ;
    USE SIGNAL ;
    ANTENNAGATEAREA 0.213000 ;
    ANTENNADIFFAREA 0.434700 ;
    PORT
      LAYER met3 ;
        RECT 0.000 289.720 4.000 290.320 ;
    END
  END wd3[8]
  PIN wd3[9]
    DIRECTION INPUT ;
    USE SIGNAL ;
    ANTENNAGATEAREA 0.213000 ;
    ANTENNADIFFAREA 0.434700 ;
    PORT
      LAYER met3 ;
        RECT 0.000 282.920 4.000 283.520 ;
    END
  END wd3[9]
  PIN we3
    DIRECTION INPUT ;
    USE SIGNAL ;
    ANTENNAGATEAREA 0.213000 ;
    ANTENNADIFFAREA 0.434700 ;
    PORT
      LAYER met3 ;
        RECT 0.000 10.920 4.000 11.520 ;
    END
  END we3
  OBS
      LAYER nwell ;
        RECT 5.330 10.795 344.270 337.365 ;
      LAYER li1 ;
        RECT 5.520 10.795 344.080 337.365 ;
      LAYER met1 ;
        RECT 4.670 9.900 345.850 337.520 ;
      LAYER met2 ;
        RECT 4.690 9.870 345.820 344.605 ;
      LAYER met3 ;
        RECT 4.400 343.720 346.000 344.585 ;
        RECT 4.000 338.320 346.000 343.720 ;
        RECT 4.400 336.920 346.000 338.320 ;
        RECT 4.000 331.520 346.000 336.920 ;
        RECT 4.400 330.120 346.000 331.520 ;
        RECT 4.000 324.720 346.000 330.120 ;
        RECT 4.400 323.320 346.000 324.720 ;
        RECT 4.000 317.920 346.000 323.320 ;
        RECT 4.400 316.520 346.000 317.920 ;
        RECT 4.000 311.120 346.000 316.520 ;
        RECT 4.400 309.720 346.000 311.120 ;
        RECT 4.000 304.320 346.000 309.720 ;
        RECT 4.400 302.920 345.600 304.320 ;
        RECT 4.000 301.600 346.000 302.920 ;
        RECT 4.000 300.200 345.600 301.600 ;
        RECT 4.000 298.880 346.000 300.200 ;
        RECT 4.000 297.520 345.600 298.880 ;
        RECT 4.400 297.480 345.600 297.520 ;
        RECT 4.400 296.160 346.000 297.480 ;
        RECT 4.400 296.120 345.600 296.160 ;
        RECT 4.000 294.760 345.600 296.120 ;
        RECT 4.000 293.440 346.000 294.760 ;
        RECT 4.000 292.040 345.600 293.440 ;
        RECT 4.000 290.720 346.000 292.040 ;
        RECT 4.400 289.320 345.600 290.720 ;
        RECT 4.000 288.000 346.000 289.320 ;
        RECT 4.000 286.600 345.600 288.000 ;
        RECT 4.000 285.280 346.000 286.600 ;
        RECT 4.000 283.920 345.600 285.280 ;
        RECT 4.400 283.880 345.600 283.920 ;
        RECT 4.400 282.560 346.000 283.880 ;
        RECT 4.400 282.520 345.600 282.560 ;
        RECT 4.000 281.160 345.600 282.520 ;
        RECT 4.000 279.840 346.000 281.160 ;
        RECT 4.000 278.440 345.600 279.840 ;
        RECT 4.000 277.120 346.000 278.440 ;
        RECT 4.400 275.720 345.600 277.120 ;
        RECT 4.000 274.400 346.000 275.720 ;
        RECT 4.000 273.000 345.600 274.400 ;
        RECT 4.000 271.680 346.000 273.000 ;
        RECT 4.000 270.320 345.600 271.680 ;
        RECT 4.400 270.280 345.600 270.320 ;
        RECT 4.400 268.960 346.000 270.280 ;
        RECT 4.400 268.920 345.600 268.960 ;
        RECT 4.000 267.560 345.600 268.920 ;
        RECT 4.000 266.240 346.000 267.560 ;
        RECT 4.000 264.840 345.600 266.240 ;
        RECT 4.000 263.520 346.000 264.840 ;
        RECT 4.400 262.120 345.600 263.520 ;
        RECT 4.000 260.800 346.000 262.120 ;
        RECT 4.000 259.400 345.600 260.800 ;
        RECT 4.000 258.080 346.000 259.400 ;
        RECT 4.000 256.720 345.600 258.080 ;
        RECT 4.400 256.680 345.600 256.720 ;
        RECT 4.400 255.360 346.000 256.680 ;
        RECT 4.400 255.320 345.600 255.360 ;
        RECT 4.000 253.960 345.600 255.320 ;
        RECT 4.000 252.640 346.000 253.960 ;
        RECT 4.000 251.240 345.600 252.640 ;
        RECT 4.000 249.920 346.000 251.240 ;
        RECT 4.400 248.520 345.600 249.920 ;
        RECT 4.000 247.200 346.000 248.520 ;
        RECT 4.000 245.800 345.600 247.200 ;
        RECT 4.000 244.480 346.000 245.800 ;
        RECT 4.000 243.120 345.600 244.480 ;
        RECT 4.400 243.080 345.600 243.120 ;
        RECT 4.400 241.760 346.000 243.080 ;
        RECT 4.400 241.720 345.600 241.760 ;
        RECT 4.000 240.360 345.600 241.720 ;
        RECT 4.000 239.040 346.000 240.360 ;
        RECT 4.000 237.640 345.600 239.040 ;
        RECT 4.000 236.320 346.000 237.640 ;
        RECT 4.400 234.920 345.600 236.320 ;
        RECT 4.000 233.600 346.000 234.920 ;
        RECT 4.000 232.200 345.600 233.600 ;
        RECT 4.000 230.880 346.000 232.200 ;
        RECT 4.000 229.520 345.600 230.880 ;
        RECT 4.400 229.480 345.600 229.520 ;
        RECT 4.400 228.160 346.000 229.480 ;
        RECT 4.400 228.120 345.600 228.160 ;
        RECT 4.000 226.760 345.600 228.120 ;
        RECT 4.000 225.440 346.000 226.760 ;
        RECT 4.000 224.040 345.600 225.440 ;
        RECT 4.000 222.720 346.000 224.040 ;
        RECT 4.400 221.320 345.600 222.720 ;
        RECT 4.000 220.000 346.000 221.320 ;
        RECT 4.000 218.600 345.600 220.000 ;
        RECT 4.000 217.280 346.000 218.600 ;
        RECT 4.000 215.920 345.600 217.280 ;
        RECT 4.400 215.880 345.600 215.920 ;
        RECT 4.400 214.560 346.000 215.880 ;
        RECT 4.400 214.520 345.600 214.560 ;
        RECT 4.000 213.160 345.600 214.520 ;
        RECT 4.000 211.840 346.000 213.160 ;
        RECT 4.000 210.440 345.600 211.840 ;
        RECT 4.000 209.120 346.000 210.440 ;
        RECT 4.400 207.720 345.600 209.120 ;
        RECT 4.000 206.400 346.000 207.720 ;
        RECT 4.000 205.000 345.600 206.400 ;
        RECT 4.000 203.680 346.000 205.000 ;
        RECT 4.000 202.320 345.600 203.680 ;
        RECT 4.400 202.280 345.600 202.320 ;
        RECT 4.400 200.960 346.000 202.280 ;
        RECT 4.400 200.920 345.600 200.960 ;
        RECT 4.000 199.560 345.600 200.920 ;
        RECT 4.000 198.240 346.000 199.560 ;
        RECT 4.000 196.840 345.600 198.240 ;
        RECT 4.000 195.520 346.000 196.840 ;
        RECT 4.400 194.120 345.600 195.520 ;
        RECT 4.000 192.800 346.000 194.120 ;
        RECT 4.000 191.400 345.600 192.800 ;
        RECT 4.000 190.080 346.000 191.400 ;
        RECT 4.000 188.720 345.600 190.080 ;
        RECT 4.400 188.680 345.600 188.720 ;
        RECT 4.400 187.360 346.000 188.680 ;
        RECT 4.400 187.320 345.600 187.360 ;
        RECT 4.000 185.960 345.600 187.320 ;
        RECT 4.000 184.640 346.000 185.960 ;
        RECT 4.000 183.240 345.600 184.640 ;
        RECT 4.000 181.920 346.000 183.240 ;
        RECT 4.400 180.520 345.600 181.920 ;
        RECT 4.000 179.200 346.000 180.520 ;
        RECT 4.000 177.800 345.600 179.200 ;
        RECT 4.000 176.480 346.000 177.800 ;
        RECT 4.000 175.120 345.600 176.480 ;
        RECT 4.400 175.080 345.600 175.120 ;
        RECT 4.400 173.760 346.000 175.080 ;
        RECT 4.400 173.720 345.600 173.760 ;
        RECT 4.000 172.360 345.600 173.720 ;
        RECT 4.000 171.040 346.000 172.360 ;
        RECT 4.000 169.640 345.600 171.040 ;
        RECT 4.000 168.320 346.000 169.640 ;
        RECT 4.400 166.920 345.600 168.320 ;
        RECT 4.000 165.600 346.000 166.920 ;
        RECT 4.000 164.200 345.600 165.600 ;
        RECT 4.000 162.880 346.000 164.200 ;
        RECT 4.000 161.520 345.600 162.880 ;
        RECT 4.400 161.480 345.600 161.520 ;
        RECT 4.400 160.160 346.000 161.480 ;
        RECT 4.400 160.120 345.600 160.160 ;
        RECT 4.000 158.760 345.600 160.120 ;
        RECT 4.000 157.440 346.000 158.760 ;
        RECT 4.000 156.040 345.600 157.440 ;
        RECT 4.000 154.720 346.000 156.040 ;
        RECT 4.400 153.320 345.600 154.720 ;
        RECT 4.000 152.000 346.000 153.320 ;
        RECT 4.000 150.600 345.600 152.000 ;
        RECT 4.000 149.280 346.000 150.600 ;
        RECT 4.000 147.920 345.600 149.280 ;
        RECT 4.400 147.880 345.600 147.920 ;
        RECT 4.400 146.560 346.000 147.880 ;
        RECT 4.400 146.520 345.600 146.560 ;
        RECT 4.000 145.160 345.600 146.520 ;
        RECT 4.000 143.840 346.000 145.160 ;
        RECT 4.000 142.440 345.600 143.840 ;
        RECT 4.000 141.120 346.000 142.440 ;
        RECT 4.400 139.720 345.600 141.120 ;
        RECT 4.000 138.400 346.000 139.720 ;
        RECT 4.000 137.000 345.600 138.400 ;
        RECT 4.000 135.680 346.000 137.000 ;
        RECT 4.000 134.320 345.600 135.680 ;
        RECT 4.400 134.280 345.600 134.320 ;
        RECT 4.400 132.960 346.000 134.280 ;
        RECT 4.400 132.920 345.600 132.960 ;
        RECT 4.000 131.560 345.600 132.920 ;
        RECT 4.000 130.240 346.000 131.560 ;
        RECT 4.000 128.840 345.600 130.240 ;
        RECT 4.000 127.520 346.000 128.840 ;
        RECT 4.400 126.120 345.600 127.520 ;
        RECT 4.000 124.800 346.000 126.120 ;
        RECT 4.000 123.400 345.600 124.800 ;
        RECT 4.000 122.080 346.000 123.400 ;
        RECT 4.000 120.720 345.600 122.080 ;
        RECT 4.400 120.680 345.600 120.720 ;
        RECT 4.400 119.360 346.000 120.680 ;
        RECT 4.400 119.320 345.600 119.360 ;
        RECT 4.000 117.960 345.600 119.320 ;
        RECT 4.000 116.640 346.000 117.960 ;
        RECT 4.000 115.240 345.600 116.640 ;
        RECT 4.000 113.920 346.000 115.240 ;
        RECT 4.400 112.520 345.600 113.920 ;
        RECT 4.000 111.200 346.000 112.520 ;
        RECT 4.000 109.800 345.600 111.200 ;
        RECT 4.000 108.480 346.000 109.800 ;
        RECT 4.000 107.120 345.600 108.480 ;
        RECT 4.400 107.080 345.600 107.120 ;
        RECT 4.400 105.760 346.000 107.080 ;
        RECT 4.400 105.720 345.600 105.760 ;
        RECT 4.000 104.360 345.600 105.720 ;
        RECT 4.000 103.040 346.000 104.360 ;
        RECT 4.000 101.640 345.600 103.040 ;
        RECT 4.000 100.320 346.000 101.640 ;
        RECT 4.400 98.920 345.600 100.320 ;
        RECT 4.000 97.600 346.000 98.920 ;
        RECT 4.000 96.200 345.600 97.600 ;
        RECT 4.000 94.880 346.000 96.200 ;
        RECT 4.000 93.520 345.600 94.880 ;
        RECT 4.400 93.480 345.600 93.520 ;
        RECT 4.400 92.160 346.000 93.480 ;
        RECT 4.400 92.120 345.600 92.160 ;
        RECT 4.000 90.760 345.600 92.120 ;
        RECT 4.000 89.440 346.000 90.760 ;
        RECT 4.000 88.040 345.600 89.440 ;
        RECT 4.000 86.720 346.000 88.040 ;
        RECT 4.400 85.320 345.600 86.720 ;
        RECT 4.000 84.000 346.000 85.320 ;
        RECT 4.000 82.600 345.600 84.000 ;
        RECT 4.000 81.280 346.000 82.600 ;
        RECT 4.000 79.920 345.600 81.280 ;
        RECT 4.400 79.880 345.600 79.920 ;
        RECT 4.400 78.560 346.000 79.880 ;
        RECT 4.400 78.520 345.600 78.560 ;
        RECT 4.000 77.160 345.600 78.520 ;
        RECT 4.000 75.840 346.000 77.160 ;
        RECT 4.000 74.440 345.600 75.840 ;
        RECT 4.000 73.120 346.000 74.440 ;
        RECT 4.400 71.720 345.600 73.120 ;
        RECT 4.000 70.400 346.000 71.720 ;
        RECT 4.000 69.000 345.600 70.400 ;
        RECT 4.000 67.680 346.000 69.000 ;
        RECT 4.000 66.320 345.600 67.680 ;
        RECT 4.400 66.280 345.600 66.320 ;
        RECT 4.400 64.960 346.000 66.280 ;
        RECT 4.400 64.920 345.600 64.960 ;
        RECT 4.000 63.560 345.600 64.920 ;
        RECT 4.000 62.240 346.000 63.560 ;
        RECT 4.000 60.840 345.600 62.240 ;
        RECT 4.000 59.520 346.000 60.840 ;
        RECT 4.400 58.120 345.600 59.520 ;
        RECT 4.000 56.800 346.000 58.120 ;
        RECT 4.000 55.400 345.600 56.800 ;
        RECT 4.000 54.080 346.000 55.400 ;
        RECT 4.000 52.720 345.600 54.080 ;
        RECT 4.400 52.680 345.600 52.720 ;
        RECT 4.400 51.360 346.000 52.680 ;
        RECT 4.400 51.320 345.600 51.360 ;
        RECT 4.000 49.960 345.600 51.320 ;
        RECT 4.000 48.640 346.000 49.960 ;
        RECT 4.000 47.240 345.600 48.640 ;
        RECT 4.000 45.920 346.000 47.240 ;
        RECT 4.400 44.520 345.600 45.920 ;
        RECT 4.000 39.120 346.000 44.520 ;
        RECT 4.400 37.720 346.000 39.120 ;
        RECT 4.000 32.320 346.000 37.720 ;
        RECT 4.400 30.920 346.000 32.320 ;
        RECT 4.000 25.520 346.000 30.920 ;
        RECT 4.400 24.120 346.000 25.520 ;
        RECT 4.000 18.720 346.000 24.120 ;
        RECT 4.400 17.320 346.000 18.720 ;
        RECT 4.000 11.920 346.000 17.320 ;
        RECT 4.400 10.520 346.000 11.920 ;
        RECT 4.000 5.120 346.000 10.520 ;
        RECT 4.400 4.260 346.000 5.120 ;
      LAYER met4 ;
        RECT 8.575 10.240 14.320 330.305 ;
        RECT 16.720 10.240 17.620 330.305 ;
        RECT 20.020 10.240 64.320 330.305 ;
        RECT 66.720 10.240 67.620 330.305 ;
        RECT 70.020 10.240 114.320 330.305 ;
        RECT 116.720 10.240 117.620 330.305 ;
        RECT 120.020 10.240 164.320 330.305 ;
        RECT 166.720 10.240 167.620 330.305 ;
        RECT 170.020 10.240 214.320 330.305 ;
        RECT 216.720 10.240 217.620 330.305 ;
        RECT 220.020 10.240 264.320 330.305 ;
        RECT 266.720 10.240 267.620 330.305 ;
        RECT 270.020 10.240 314.320 330.305 ;
        RECT 316.720 10.240 317.620 330.305 ;
        RECT 320.020 10.240 338.265 330.305 ;
        RECT 8.575 4.255 338.265 10.240 ;
      LAYER met5 ;
        RECT 61.300 147.100 292.900 148.700 ;
  END
END RegFileALU
END LIBRARY

